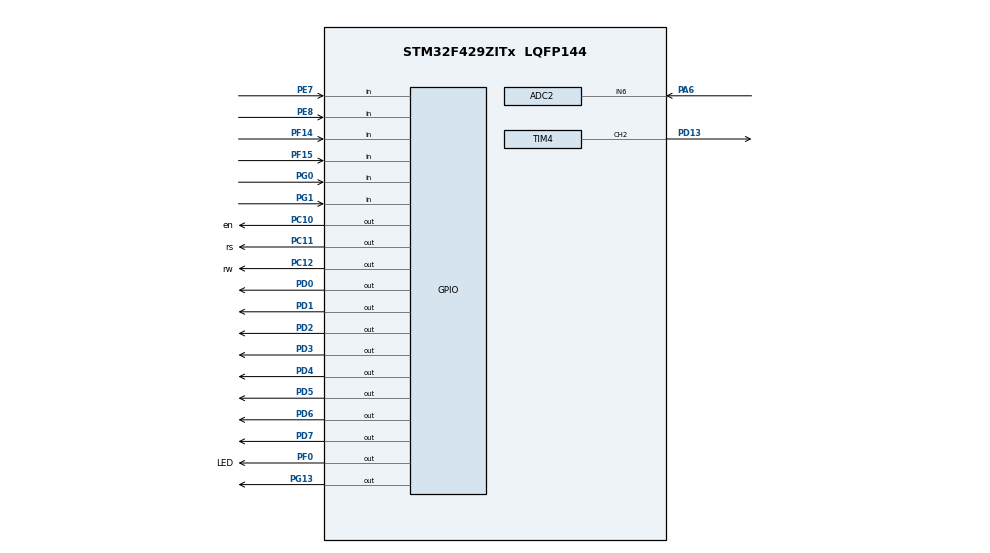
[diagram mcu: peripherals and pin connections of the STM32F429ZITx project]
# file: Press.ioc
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ADC2.Channel-0\#ChannelRegularConversion=ADC_CHANNEL_6
ADC2.ClockPrescaler=ADC_CLOCK_SYNC_PCLK_DIV4
ADC2.NbrOfConversionFlag=1
ADC2.Rank-0\#ChannelRegularConversion=1
ADC2.SamplingTime-0\#ChannelRegularConversion=ADC_SAMPLETIME_3CYCLES
Mcu.Family=STM32F4
Mcu.Name=STM32F429ZITx
Mcu.Package=LQFP144
NVIC.ADC_IRQn=true\:0\:0\:false\:false\:true\:true\:true
NVIC.PriorityGroup=NVIC_PRIORITYGROUP_4
PA13.Mode=Trace_Asynchronous_SW
PA13.Signal=SYS_JTMS-SWDIO
PA14.Mode=Trace_Asynchronous_SW
PA14.Signal=SYS_JTCK-SWCLK
PA6.Signal=ADCx_IN6
PB3.Mode=Trace_Asynchronous_SW
PB3.Signal=SYS_JTDO-SWO
PC10.GPIO_Label=en
PC10.Signal=GPIO_Output
PC11.GPIO_Label=rs
PC11.Signal=GPIO_Output
PC12.GPIO_Label=rw
PC12.Signal=GPIO_Output
PD0.Signal=GPIO_Output
PD1.Signal=GPIO_Output
PD13.Signal=S_TIM4_CH2
PD2.Signal=GPIO_Output
PD3.Signal=GPIO_Output
PD4.Signal=GPIO_Output
PD5.Signal=GPIO_Output
PD6.Signal=GPIO_Output
PD7.Signal=GPIO_Output
PE7.Signal=GPIO_Input
PE8.Signal=GPIO_Input
PF0.GPIO_Label=LED
PF0.Signal=GPIO_Output
PF14.Signal=GPIO_Input
PF15.Signal=GPIO_Input
PG0.Signal=GPIO_Input
PG1.Signal=GPIO_Input
PG13.Signal=GPIO_Output
PH0/OSC_IN.Mode=HSE-External-Oscillator
PH0/OSC_IN.Signal=RCC_OSC_IN
PH1/OSC_OUT.Mode=HSE-External-Oscillator
PH1/OSC_OUT.Signal=RCC_OSC_OUT
ProjectManager.HeapSize=0x200
ProjectManager.StackSize=0x400
ProjectManager.TargetToolchain=EWARM V8
RCC.48MHZClocksFreq_Value=50000000
RCC.AHBFreq_Value=100000000
RCC.APB1CLKDivider=RCC_HCLK_DIV4
RCC.APB1Freq_Value=25000000
RCC.APB1TimFreq_Value=50000000
RCC.APB2CLKDivider=RCC_HCLK_DIV2
RCC.APB2Freq_Value=50000000
RCC.APB2TimFreq_Value=100000000
RCC.CortexFreq_Value=100000000
RCC.HCLKFreq_Value=100000000
RCC.HSE_VALUE=16000000
RCC.HSI_VALUE=16000000
RCC.LSE_VALUE=32768
RCC.PLLM=8
RCC.PLLN=100
RCC.PLLSourceVirtual=RCC_PLLSOURCE_HSE
RCC.SYSCLKFreq_VALUE=100000000
RCC.SYSCLKSource=RCC_SYSCLKSOURCE_PLLCLK
RCC.VCOOutputFreq_Value=200000000
SH.ADCx_IN6.0=ADC2_IN6,IN6
SH.S_TIM4_CH2.0=TIM4_CH2,PWM Generation2 CH2
TIM4.Channel-PWM\ Generation2\ CH2=TIM_CHANNEL_2
TIM4.Period=0xFFFF
TIM4.Prescaler=7
board=custom

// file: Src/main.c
/* USER CODE BEGIN Header */
/**
  ******************************************************************************
  * @file           : main.c
  * @brief          : Main program body
  ******************************************************************************
  ** This notice applies to any and all portions of this file
  * that are not between comment pairs USER CODE BEGIN and
  * USER CODE END. Other portions of this file, whether
  * inserted by the user or by software development tools
  * are owned by their respective copyright owners.
  *
  * COPYRIGHT(c) 2019 STMicroelectronics
  *
  * Redistribution and use in source and binary forms, with or without modification,
  * are permitted provided that the following conditions are met:
  *   1. Redistributions of source code must retain the above copyright notice,
  *      this list of conditions and the following disclaimer.
  *   2. Redistributions in binary form must reproduce the above copyright notice,
  *      this list of conditions and the following disclaimer in the documentation
  *      and/or other materials provided with the distribution.
  *   3. Neither the name of STMicroelectronics nor the names of its contributors
  *      may be used to endorse or promote products derived from this software
  *      without specific prior written permission.
  *
  * THIS SOFTWARE IS PROVIDED BY THE COPYRIGHT HOLDERS AND CONTRIBUTORS "AS IS"
  * AND ANY EXPRESS OR IMPLIED WARRANTIES, INCLUDING, BUT NOT LIMITED TO, THE
  * IMPLIED WARRANTIES OF MERCHANTABILITY AND FITNESS FOR A PARTICULAR PURPOSE ARE
  * DISCLAIMED. IN NO EVENT SHALL THE COPYRIGHT HOLDER OR CONTRIBUTORS BE LIABLE
  * FOR ANY DIRECT, INDIRECT, INCIDENTAL, SPECIAL, EXEMPLARY, OR CONSEQUENTIAL
  * DAMAGES (INCLUDING, BUT NOT LIMITED TO, PROCUREMENT OF SUBSTITUTE GOODS OR
  * SERVICES; LOSS OF USE, DATA, OR PROFITS; OR BUSINESS INTERRUPTION) HOWEVER
  * CAUSED AND ON ANY THEORY OF LIABILITY, WHETHER IN CONTRACT, STRICT LIABILITY,
  * OR TORT (INCLUDING NEGLIGENCE OR OTHERWISE) ARISING IN ANY WAY OUT OF THE USE
  * OF THIS SOFTWARE, EVEN IF ADVISED OF THE POSSIBILITY OF SUCH DAMAGE.
  *
  ******************************************************************************
  */
/* USER CODE END Header */

#include "main.h"

/* USER CODE BEGIN Includes */
#include <math.h>
/* USER CODE END Includes */

ADC_HandleTypeDef hadc2;

TIM_HandleTypeDef htim4;

/* USER CODE BEGIN PV */
uint32_t tempValue = 0;
double tempK = 0;
double tempC = 0;
double tempF = 0;
double kp, ki, kd;
uint32_t currentTime, previousTime;
double elapsedTime;
double setPoint = 70;
double error, cumError, rateError, lastError;
unsigned char counter = 0;
unsigned int myPID = 0;
uint32_t finalAdc, beginAdc, adcTime;
/* USER CODE END PV */

void SystemClock_Config(void);
static void MX_GPIO_Init(void);
static void MX_ADC2_Init(void);
static void MX_TIM4_Init(void);
/* USER CODE BEGIN PFP */
int computePID(double inp);

/* USER CODE END PFP */

int main(void)
{

  /* MCU Configuration--------------------------------------------------------*/

  /* Reset of all peripherals, Initializes the Flash interface and the Systick. */
  HAL_Init();

  /* Configure the system clock */
  SystemClock_Config();

  /* Initialize all configured peripherals */
  MX_GPIO_Init();
  MX_ADC2_Init();
  MX_TIM4_Init();
  /* USER CODE BEGIN 2 */
  HAL_ADC_Start_IT(&hadc2);
  //Use PWM to control? or simple loop?
  kp = 19.56;
  ki = 0.71;
  kd = 134.26;
  TIM4->CCR2 = 300;
  HAL_TIM_PWM_Start(&htim4, TIM_CHANNEL_2);

  /* USER CODE END 2 */

  /* Infinite loop */
  /* USER CODE BEGIN WHILE */
  while (1)
  {
    if(counter==0){
      myPID = computePID(tempF);
      TIM4->CCR2 = (int)myPID;
      HAL_Delay(200);
      TIM4->CCR2 = 0;
      HAL_Delay(200);
    }
    /* USER CODE END WHILE */

  }
}

void SystemClock_Config(void)
{
  RCC_OscInitTypeDef RCC_OscInitStruct = {0};
  RCC_ClkInitTypeDef RCC_ClkInitStruct = {0};

  /**Configure the main internal regulator output voltage
  */
  __HAL_RCC_PWR_CLK_ENABLE();
  __HAL_PWR_VOLTAGESCALING_CONFIG(PWR_REGULATOR_VOLTAGE_SCALE3);
  /**Initializes the CPU, AHB and APB busses clocks
  */
  RCC_OscInitStruct.OscillatorType = RCC_OSCILLATORTYPE_HSE;
  RCC_OscInitStruct.HSEState = RCC_HSE_ON;
  RCC_OscInitStruct.PLL.PLLState = RCC_PLL_ON;
  RCC_OscInitStruct.PLL.PLLSource = RCC_PLLSOURCE_HSE;
  RCC_OscInitStruct.PLL.PLLM = 4;
  RCC_OscInitStruct.PLL.PLLN = 100;
  RCC_OscInitStruct.PLL.PLLP = RCC_PLLP_DIV2;
  RCC_OscInitStruct.PLL.PLLQ = 4;
  if (HAL_RCC_OscConfig(&RCC_OscInitStruct) != HAL_OK)
  {
    Error_Handler();
  }
  /**Initializes the CPU, AHB and APB busses clocks
  */
  RCC_ClkInitStruct.ClockType = RCC_CLOCKTYPE_HCLK|RCC_CLOCKTYPE_SYSCLK
                              |RCC_CLOCKTYPE_PCLK1|RCC_CLOCKTYPE_PCLK2;
  RCC_ClkInitStruct.SYSCLKSource = RCC_SYSCLKSOURCE_PLLCLK;
  RCC_ClkInitStruct.AHBCLKDivider = RCC_SYSCLK_DIV1;
  RCC_ClkInitStruct.APB1CLKDivider = RCC_HCLK_DIV4;
  RCC_ClkInitStruct.APB2CLKDivider = RCC_HCLK_DIV2;

  if (HAL_RCC_ClockConfig(&RCC_ClkInitStruct, FLASH_LATENCY_3) != HAL_OK)
  {
    Error_Handler();
  }
}

static void MX_ADC2_Init(void)
{

  ADC_ChannelConfTypeDef sConfig = {0};

  /**Configure the global features of the ADC (Clock, Resolution, Data Alignment and number of conversion)
  */
  hadc2.Instance = ADC2;
  hadc2.Init.ClockPrescaler = ADC_CLOCK_SYNC_PCLK_DIV4;
  hadc2.Init.Resolution = ADC_RESOLUTION_12B;
  hadc2.Init.ScanConvMode = DISABLE;
  hadc2.Init.ContinuousConvMode = DISABLE;
  hadc2.Init.DiscontinuousConvMode = DISABLE;
  hadc2.Init.ExternalTrigConvEdge = ADC_EXTERNALTRIGCONVEDGE_NONE;
  hadc2.Init.ExternalTrigConv = ADC_SOFTWARE_START;
  hadc2.Init.DataAlign = ADC_DATAALIGN_RIGHT;
  hadc2.Init.NbrOfConversion = 1;
  hadc2.Init.DMAContinuousRequests = DISABLE;
  hadc2.Init.EOCSelection = ADC_EOC_SINGLE_CONV;
  if (HAL_ADC_Init(&hadc2) != HAL_OK)
  {
    Error_Handler();
  }
  /**Configure for the selected ADC regular channel its corresponding rank in the sequencer and its sample time.
  */
  sConfig.Channel = ADC_CHANNEL_6;
  sConfig.Rank = 1;
  sConfig.SamplingTime = ADC_SAMPLETIME_3CYCLES;
  if (HAL_ADC_ConfigChannel(&hadc2, &sConfig) != HAL_OK)
  {
    Error_Handler();
  }

}

static void MX_TIM4_Init(void)
{

  TIM_MasterConfigTypeDef sMasterConfig = {0};
  TIM_OC_InitTypeDef sConfigOC = {0};

  htim4.Instance = TIM4;
  htim4.Init.Prescaler = 7;
  htim4.Init.CounterMode = TIM_COUNTERMODE_UP;
  htim4.Init.Period = 0xFFFF;
  htim4.Init.ClockDivision = TIM_CLOCKDIVISION_DIV1;
  if (HAL_TIM_PWM_Init(&htim4) != HAL_OK)
  {
    Error_Handler();
  }
  sMasterConfig.MasterOutputTrigger = TIM_TRGO_RESET;
  sMasterConfig.MasterSlaveMode = TIM_MASTERSLAVEMODE_DISABLE;
  if (HAL_TIMEx_MasterConfigSynchronization(&htim4, &sMasterConfig) != HAL_OK)
  {
    Error_Handler();
  }
  sConfigOC.OCMode = TIM_OCMODE_PWM1;
  sConfigOC.Pulse = 0;
  sConfigOC.OCPolarity = TIM_OCPOLARITY_HIGH;
  sConfigOC.OCFastMode = TIM_OCFAST_DISABLE;
  if (HAL_TIM_PWM_ConfigChannel(&htim4, &sConfigOC, TIM_CHANNEL_2) != HAL_OK)
  {
    Error_Handler();
  }
  HAL_TIM_MspPostInit(&htim4);

}

static void MX_GPIO_Init(void)
{
  GPIO_InitTypeDef GPIO_InitStruct = {0};

  /* GPIO Ports Clock Enable */
  __HAL_RCC_GPIOH_CLK_ENABLE();
  __HAL_RCC_GPIOA_CLK_ENABLE();
  __HAL_RCC_GPIOD_CLK_ENABLE();
  __HAL_RCC_GPIOG_CLK_ENABLE();
  __HAL_RCC_GPIOB_CLK_ENABLE();

  /*Configure GPIO pin Output Level */
  HAL_GPIO_WritePin(GPIOG, GPIO_PIN_13, GPIO_PIN_RESET);

  /*Configure GPIO pin : PG13 */
  GPIO_InitStruct.Pin = GPIO_PIN_13;
  GPIO_InitStruct.Mode = GPIO_MODE_OUTPUT_PP;
  GPIO_InitStruct.Pull = GPIO_NOPULL;
  GPIO_InitStruct.Speed = GPIO_SPEED_FREQ_LOW;
  HAL_GPIO_Init(GPIOG, &GPIO_InitStruct);

}

/* USER CODE BEGIN 4 */

void HAL_ADC_ConvCpltCallback(ADC_HandleTypeDef* hadc){
  tempValue = HAL_ADC_GetValue(&hadc2);

  tempK = 1.0/((1.0/298.15)+((1.0/4390.0)*(log(((4096.0/(double)tempValue)-1.0)))));//B value equation to calculate temprature of thermistor
  tempC = tempK - 273.15; //K to C
  tempF = ((9.0*tempC)/5.0)+32.0; //C to F
  tempF = tempF+20;

  HAL_ADC_Start_IT(&hadc2);

}

int computePID(double inp){
  currentTime = HAL_GetTick();                //get current time
  elapsedTime = (double)(currentTime - previousTime);        //compute time elapsed from previous computation

  error = setPoint - inp;                                // determine error
  cumError += error * elapsedTime;                // compute integral
  rateError = (error - lastError)/elapsedTime;   // compute derivative
  double out;
  if(cumError < -0xFFFF){
    cumError = -0xFFFF;                                      //Clamping
  }
  if(cumError > 0xFFFF){
    cumError = 0xFFFF;                                       //Clamping
  }

  out = kp*error + ki*cumError + kd*rateError;

  if(out < 0){
    out = 0;
  }
  if(out > 0xFFFF){
    out = 0xFFFF;
  }
  lastError = error;                                //remember current error
  previousTime = currentTime;                        //remember current time

  return (int)out;

}

/* USER CODE END 4 */

void Error_Handler(void)
{
}

/************************ (C) COPYRIGHT STMicroelectronics *****END OF FILE****/
